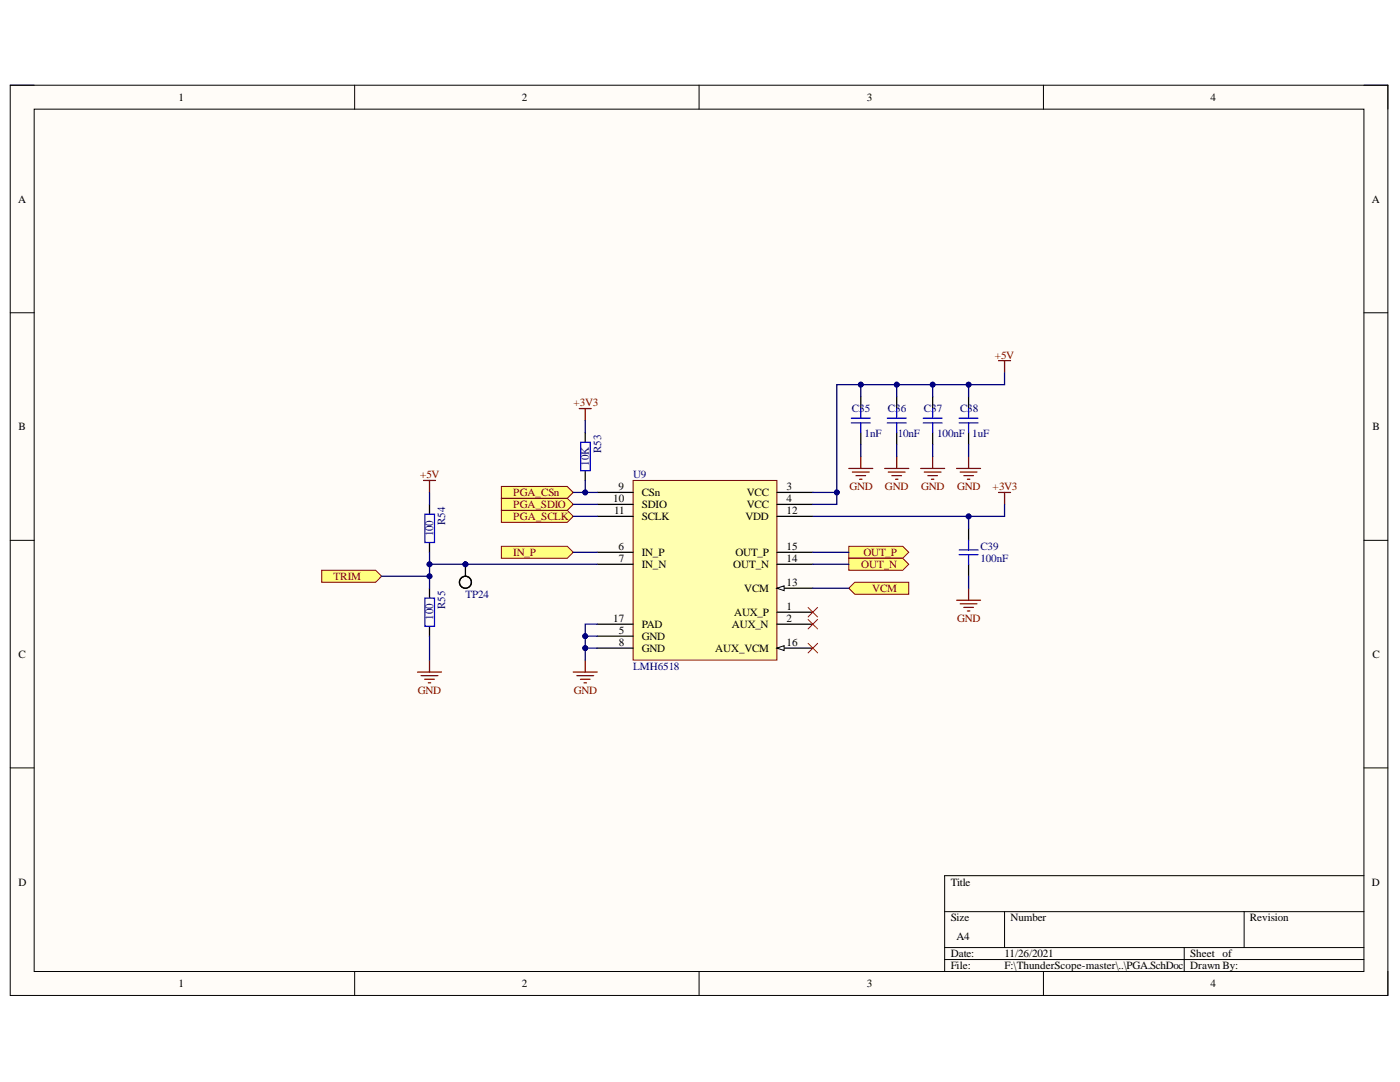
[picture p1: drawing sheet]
<svg xmlns="http://www.w3.org/2000/svg" width="279mm" height="216mm" viewBox="0 0 279 216" stroke-linecap="round" stroke-linejoin="round" font-family="sans-serif">
<defs><g id="words">
<g font-size="2.2">
<text x="35.6" y="20.1">1</text>
<text x="104.1" y="20.1">2</text>
<text x="173" y="20.1">3</text>
<text x="241.6" y="20.1">4</text>
<text x="3.6" y="40.4">A</text>
<text x="273.8" y="40.4">A</text>
<text x="3.7" y="85.8">B</text>
<text x="273.9" y="85.8">B</text>
<text x="122.4" y="100.2">10</text>
<text x="123.4" y="97.8">9</text>
<text x="128.1" y="99">CSn</text>
<text x="128.1" y="101.4">SDIO</text>
<text x="149" y="99">VCC</text>
<text x="149" y="101.4">VCC</text>
<text x="157" y="97.8">3</text>
<text x="157" y="100.2">4</text>
<text x="122.6" y="102.6">11</text>
<text x="128.1" y="103.8">SCLK</text>
<text x="148.8" y="103.8">VDD</text>
<text x="157" y="102.6">12</text>
<text x="123.4" y="109.8">6</text>
<text x="123.5" y="112.1">7</text>
<text x="128.1" y="110.9">IN_P</text>
<text x="128.1" y="113.4">IN_N</text>
<text x="146.3" y="113.4">OUT_N</text>
<text x="146.8" y="110.9">OUT_P</text>
<text x="157" y="112.1">14</text>
<text x="157" y="109.8">15</text>
<text x="148.5" y="118.1">VCM</text>
<text x="157" y="116.9">13</text>
<text x="122.4" y="124.1">17</text>
<text x="128.1" y="125.3">PAD</text>
<text x="146.1" y="125.3">AUX_N</text>
<text x="146.5" y="123">AUX_P</text>
<text x="157" y="121.7">1</text>
<text x="157" y="124.1">2</text>
<text x="3.7" y="131.3">C</text>
<text x="123.5" y="128.9">8</text>
<text x="123.5" y="126.5">5</text>
<text x="128.1" y="130.1">GND</text>
<text x="128.1" y="127.7">GND</text>
<text x="142.7" y="130.1">AUX_VCM</text>
<text x="157" y="128.9">16</text>
<text x="273.9" y="131.3">C</text>
<text x="3.7" y="176.7">D</text>
<text x="189.7" y="176.7">Title</text>
<text x="273.8" y="176.7">D</text>
<text x="189.7" y="183.8">Size</text>
<text x="201.7" y="183.8">Number</text>
<text x="249.4" y="183.8">Revision</text>
<text x="189.7" y="191">Date:</text>
<text x="190.9" y="187.5">A4</text>
<text x="200.5" y="191">11/26/2021</text>
<text x="237.5" y="191">Sheet of</text>
<text x="35.6" y="197">1</text>
<text x="104.1" y="197">2</text>
<text x="173" y="197">3</text>
<text x="189.7" y="193.4">File:</text>
<text x="200.5" y="193.4">F:\ThunderScope-master\..\PGA.SchDoc</text>
<text x="237.5" y="193.4">Drawn By:</text>
<text x="241.6" y="197">4</text>
</g>
<g font-size="2.2" fill="#800000">
<text x="198.5" y="71.5">+5V</text>
<text x="114.4" y="81.1">+3V3</text>
<text x="83.8" y="95.5">+5V</text>
<text x="102.4" y="99">PGA_CSn</text>
<text x="102.4" y="101.4">PGA_SDIO</text>
<text x="169.5" y="97.8">GND</text>
<text x="176.6" y="97.8">GND</text>
<text x="183.8" y="97.8">GND</text>
<text x="191" y="97.8">GND</text>
<text x="198.1" y="97.8">+3V3</text>
<text x="102.4" y="103.8">PGA_SCLK</text>
<text x="102.4" y="110.9">IN_P</text>
<text x="171.9" y="113.4">OUT_N</text>
<text x="172.3" y="110.9">OUT_P</text>
<text x="66.6" y="115.8">TRIM</text>
<text x="174.1" y="118.1">VCM</text>
<text x="191" y="124.1">GND</text>
<text x="83.4" y="138.4">GND</text>
<text x="114.5" y="138.4">GND</text>
</g>
<g font-size="2.2" fill="#000080">
<text x="170" y="82.3">C35</text>
<text x="177.2" y="82.3">C36</text>
<text x="184.4" y="82.3">C37</text>
<text x="191.6" y="82.3">C38</text>
<text x="172.6" y="87.1">1nF</text>
<text x="179.2" y="87.1">10nF</text>
<text x="187" y="87.1">100nF</text>
<text x="194" y="87.1">1uF</text>
<text x="117.5" y="92.9" transform="rotate(-90 117.5 92.9)">10K</text>
<text x="119.9" y="90.4" transform="rotate(-90 119.9 90.4)">R53</text>
<text x="126.4" y="95.5">U9</text>
<text x="86.4" y="107" transform="rotate(-90 86.4 107)">100</text>
<text x="88.8" y="104.8" transform="rotate(-90 88.8 104.8)">R54</text>
<text x="195.6" y="109.8">C39</text>
<text x="195.6" y="112.1">100nF</text>
<text x="92.9" y="119.3">TP24</text>
<text x="86.4" y="123.7" transform="rotate(-90 86.4 123.7)">100</text>
<text x="88.8" y="121.5" transform="rotate(-90 88.8 121.5)">R55</text>
<text x="126.4" y="133.7">LMH6518</text>
</g>
</g></defs>
<path d="M2 17h275v181.6h-275z" fill-rule="evenodd" fill="#fffcf8"/>
<path d="M2 17h275v181.6h-275z" fill="none" stroke="#000" stroke-width=".2"/>
<path d="M6.8 21.8h265.4v172.1h-265.4z" fill-rule="evenodd" fill="#fffcf8"/>
<g fill="none" stroke="#000" stroke-width=".2">
<path d="M2 17h4.8M70.8 17v4.8M139.5 17v4.8M208.2 17v4.8M272.2 17h4.8v4.8M6.8 21.8h265.4v172.1h-265.4zM2 62.4h4.8M272.2 62.4h4.8M2 107.8h4.8M272.2 107.8h4.8M2 153.2h4.8M272.2 153.2h4.8"/>
<path d="M272.2 174.7h-83.7v19.2M70.8 193.9v4.7M139.5 193.9v4.7M188.5 181.9h83.7M188.5 189.1h83.7M188.5 191.5h83.7M200.5 181.9v7.2M208.2 193.9v4.7M236.3 189.1v4.8M248.3 181.9v7.2M277 193.9v4.7"/>
</g>
<path d="M126.4 95.9h28.6v35.8h-28.6z" fill-rule="evenodd" fill="#ffffb0"/>
<path d="M126.4 95.9h28.6v35.8h-28.6z" fill="none" stroke="#800000" stroke-width=".2"/>
<path d="M119.2 98.3h7.2M119.2 100.6h7.2M119.2 103h7.2M155 103h7.2M155 117.4h7.2" fill="none" stroke="#000" stroke-width=".25"/>
<path d="M155 117.4l1.5-.5v1z" fill="#f8fcff"/>
<path d="M155 117.4l1.5-.5v1z" fill="none" stroke="#000" stroke-width=".2"/>
<path d="M155 112.6h7.2M155 110.2h7.2M155 122.2h7.2M155 124.5h7.2M155 129.3h7.2" fill="none" stroke="#000" stroke-width=".25"/>
<path d="M155 129.3l1.5-.5v1z" fill="#f8fcff"/>
<path d="M155 129.3l1.5-.5v1z" fill="none" stroke="#000" stroke-width=".2"/>
<path d="M155 98.3h7.2M119.2 110.2h7.2M119.2 112.6h7.2M155 100.6h7.2M119.2 129.3h7.2M119.2 126.9h7.2M119.2 124.5h7.2" fill="none" stroke="#000" stroke-width=".25"/>
<path d="M100.1 97.1h13.1l1.2 1.2-1.2 1.2h-13.1z" fill-rule="evenodd" fill="#ffff80"/>
<path d="M100.1 97.1h13.1l1.2 1.2-1.2 1.2h-13.1z" fill="none" stroke="#800000" stroke-width=".2"/>
<path d="M116.8 86.3v1.9M116.8 94v1.9" fill="none" stroke="#000" stroke-width=".25"/>
<path d="M115.9 88.3h1.9v5.6h-1.9z" fill="none" stroke="#00f" stroke-width=".25"/>
<path d="M115.6 81.5h2.4M116.8 81.5v2.4" fill="none" stroke="#800000" stroke-width=".25"/>
<path d="M100.1 101.8h13.1l1.2 1.2-1.2 1.2h-13.1z" fill-rule="evenodd" fill="#ffff80"/>
<path d="M100.1 101.8h13.1l1.2 1.2-1.2 1.2h-13.1z" fill="none" stroke="#800000" stroke-width=".2"/>
<path d="M100.1 99.5h13.1l1.2 1.1-1.2 1.2h-13.1z" fill-rule="evenodd" fill="#ffff80"/>
<path d="M100.1 99.5h13.1l1.2 1.1-1.2 1.2h-13.1z" fill="none" stroke="#800000" stroke-width=".2"/>
<path d="M100.1 109h13.1l1.2 1.2-1.2 1.2h-13.1z" fill-rule="evenodd" fill="#ffff80"/>
<path d="M100.1 109h13.1l1.2 1.2-1.2 1.2h-13.1z" fill="none" stroke="#800000" stroke-width=".2"/>
<path d="M114.4 134.1h4.8M115.1 134.8h3.4M115.8 135.5h2M116.6 136.3h.4M116.8 131.7v2.4" fill="none" stroke="#800000" stroke-width=".25"/>
<path d="M169.4 117.4l1.2-1.2h10.8v2.4h-10.8z" fill-rule="evenodd" fill="#ffff80"/>
<path d="M169.4 117.4l1.2-1.2h10.8v2.4h-10.8z" fill="none" stroke="#800000" stroke-width=".2"/>
<path d="M169.4 109h10.8l1.2 1.2-1.2 1.2h-10.8z" fill-rule="evenodd" fill="#ffff80"/>
<path d="M169.4 109h10.8l1.2 1.2-1.2 1.2h-10.8z" fill="none" stroke="#800000" stroke-width=".2"/>
<path d="M169.4 111.4h10.8l1.2 1.2-1.2 1.2h-10.8z" fill-rule="evenodd" fill="#ffff80"/>
<path d="M169.4 111.4h10.8l1.2 1.2-1.2 1.2h-10.8z" fill="none" stroke="#800000" stroke-width=".2"/>
<g fill="none" stroke="#000" stroke-width=".25">
<path d="M171.8 79.1v2.4M179 79.1v2.4M186.1 79.1v2.4M193.3 79.1v2.4M171.8 86.3v2.4M179 86.3v2.4M186.1 86.3v2.4M193.3 86.3v2.4M85.7 100.6v1.9M85.7 108.3v1.9M85.7 117.4v1.9M193.3 105.4v2.4"/>
<path d="M193.3 112.6v2.4M85.7 125.1v1.8"/>
</g>
<g fill="none" stroke="#00f" stroke-width=".25">
<path d="M169.9 84.4h3.8M169.9 83.4h3.8M171.8 81.5v1.9M171.8 84.4v1.9M177.1 84.4h3.7M177.1 83.4h3.7M179 81.5v1.9M179 84.4v1.9M184.3 84.4h3.7M184.3 83.4h3.7M186.1 81.5v1.9M186.1 84.4v1.9"/>
<path d="M191.4 84.4h3.8M191.4 83.4h3.8M193.3 81.5v1.9M193.3 84.4v1.9M84.8 102.6h1.9v5.7h-1.9zM84.8 119.3h1.9v5.7h-1.9zM191.4 110.7h3.8M191.4 109.7h3.8M193.3 107.8v1.9M193.3 110.7v1.9"/>
</g>
<g fill="none" stroke="#800000" stroke-width=".25">
<path d="M199.3 72h2.4M200.5 72v2.4M84.5 95.9h2.4M85.7 95.9v2.4M169.4 93.5h4.8M170.1 94.2h3.4M170.8 94.9h1.9M171.5 95.6h.5M171.8 91.1v2.4M176.6 93.5h4.8M177.3 94.2h3.3M178 94.9h1.9"/>
<path d="M178.7 95.6h.5M179 91.1v2.4M183.7 93.5h4.8M184.5 94.2h3.3M185.2 94.9h1.9M185.9 95.6h.5M186.1 91.1v2.4M190.9 93.5h4.8M191.6 94.2h3.4M192.4 94.9h1.9M193.1 95.6h.4M193.3 91.1v2.4"/>
<path d="M199.3 98.3h2.4M200.5 98.3v2.4M190.9 119.8h4.8M193.3 117.4v2.4M83.3 134.1h4.8M84 134.8h3.4M84.8 135.5h1.9M85.5 136.3h.5M85.7 131.7v2.4M191.6 120.5h3.4M192.4 121.2h1.9M193.1 121.9h.4"/>
</g>
<path d="M161.3 121.2l1.9 1.9M161.3 123.6l1.9 1.9M161.3 128.4l1.9 1.9M163.2 121.2l-1.9 1.9M163.2 123.6l-1.9 1.9M163.2 128.4l-1.9 1.9" fill="none" stroke="#f00" stroke-width=".2"/>
<path d="M64.2 113.8h10.8l1.2 1.2-1.2 1.2h-10.8z" fill-rule="evenodd" fill="#ffff80"/>
<path d="M64.2 113.8h10.8l1.2 1.2-1.2 1.2h-10.8z" fill="none" stroke="#800000" stroke-width=".2"/>
<path d="M193.3 76.8v2.3" fill="none" stroke="#000080" stroke-width=".25"/>
<circle cx="193.3" cy="76.7" r=".48" fill="#000080"/>
<circle cx="193.3" cy="76.7" r=".48" fill="none" stroke="#000080" stroke-width=".2"/>
<path d="M76.2 115h9.5" fill="none" stroke="#000080" stroke-width=".25"/>
<circle cx="85.7" cy="115" r=".48" fill="#000080"/>
<circle cx="85.7" cy="115" r=".48" fill="none" stroke="#000080" stroke-width=".2"/>
<path d="M85.7 112.6h33.5" fill="none" stroke="#000080" stroke-width=".25"/>
<circle cx="92.9" cy="112.6" r=".48" fill="#000080"/>
<circle cx="92.9" cy="112.6" r=".48" fill="none" stroke="#000080" stroke-width=".2"/>
<circle cx="85.7" cy="112.6" r=".48" fill="#000080"/>
<circle cx="85.7" cy="112.6" r=".48" fill="none" stroke="#000080" stroke-width=".2"/>
<path d="M114.4 98.3h4.8M114.4 110.2h4.8M114.4 103h4.8M114.4 100.6h4.8" fill="none" stroke="#000080" stroke-width=".25"/>
<circle cx="116.8" cy="98.3" r=".48" fill="#000080"/>
<circle cx="116.8" cy="98.3" r=".48" fill="none" stroke="#000080" stroke-width=".2"/>
<path d="M119.2 124.5h-2.4v4.8h2.4" fill="none" stroke="#000080" stroke-width=".25"/>
<circle cx="116.8" cy="126.9" r=".48" fill="#000080"/>
<circle cx="116.8" cy="126.9" r=".48" fill="none" stroke="#000080" stroke-width=".2"/>
<circle cx="116.8" cy="129.3" r=".48" fill="#000080"/>
<circle cx="116.8" cy="129.3" r=".48" fill="none" stroke="#000080" stroke-width=".2"/>
<path d="M116.8 126.9h2.4" fill="none" stroke="#000080" stroke-width=".25"/>
<circle cx="116.8" cy="126.9" r=".48" fill="#000080"/>
<circle cx="116.8" cy="126.9" r=".48" fill="none" stroke="#000080" stroke-width=".2"/>
<path d="M162.2 117.4h7.2M162.2 112.6h7.2M162.2 110.2h7.2M200.5 100.7v2.3h-38.3" fill="none" stroke="#000080" stroke-width=".25"/>
<circle cx="193.3" cy="103" r=".48" fill="#000080"/>
<circle cx="193.3" cy="103" r=".48" fill="none" stroke="#000080" stroke-width=".2"/>
<path d="M171.8 76.7h-4.8v23.9h-4.8" fill="none" stroke="#000080" stroke-width=".25"/>
<circle cx="171.8" cy="76.7" r=".48" fill="#000080"/>
<circle cx="171.8" cy="76.7" r=".48" fill="none" stroke="#000080" stroke-width=".2"/>
<circle cx="167" cy="98.3" r=".48" fill="#000080"/>
<circle cx="167" cy="98.3" r=".48" fill="none" stroke="#000080" stroke-width=".2"/>
<path d="M162.2 98.3h4.8" fill="none" stroke="#000080" stroke-width=".25"/>
<circle cx="167" cy="98.3" r=".48" fill="#000080"/>
<circle cx="167" cy="98.3" r=".48" fill="none" stroke="#000080" stroke-width=".2"/>
<path d="M179 76.8h-7.2v2.3" fill="none" stroke="#000080" stroke-width=".25"/>
<circle cx="171.8" cy="76.7" r=".48" fill="#000080"/>
<circle cx="171.8" cy="76.7" r=".48" fill="none" stroke="#000080" stroke-width=".2"/>
<circle cx="179" cy="76.7" r=".48" fill="#000080"/>
<circle cx="179" cy="76.7" r=".48" fill="none" stroke="#000080" stroke-width=".2"/>
<path d="M186.1 76.8h-7.1v2.3" fill="none" stroke="#000080" stroke-width=".25"/>
<circle cx="179" cy="76.7" r=".48" fill="#000080"/>
<circle cx="179" cy="76.7" r=".48" fill="none" stroke="#000080" stroke-width=".2"/>
<circle cx="186.1" cy="76.7" r=".48" fill="#000080"/>
<circle cx="186.1" cy="76.7" r=".48" fill="none" stroke="#000080" stroke-width=".2"/>
<path d="M200.5 74.4v2.4h-14.4v2.3" fill="none" stroke="#000080" stroke-width=".25"/>
<circle cx="186.1" cy="76.7" r=".48" fill="#000080"/>
<circle cx="186.1" cy="76.7" r=".48" fill="none" stroke="#000080" stroke-width=".2"/>
<circle cx="193.3" cy="76.7" r=".48" fill="#000080"/>
<circle cx="193.3" cy="76.7" r=".48" fill="none" stroke="#000080" stroke-width=".2"/>
<path d="M85.7 110.2v7.2M85.7 126.9v4.8" fill="none" stroke="#000080" stroke-width=".25"/>
<circle cx="85.7" cy="115" r=".48" fill="#000080"/>
<circle cx="85.7" cy="115" r=".48" fill="none" stroke="#000080" stroke-width=".2"/>
<circle cx="85.7" cy="112.6" r=".48" fill="#000080"/>
<circle cx="85.7" cy="112.6" r=".48" fill="none" stroke="#000080" stroke-width=".2"/>
<path d="M85.7 98.3v2.3M116.8 129.3v2.4" fill="none" stroke="#000080" stroke-width=".25"/>
<circle cx="116.8" cy="129.3" r=".48" fill="#000080"/>
<circle cx="116.8" cy="129.3" r=".48" fill="none" stroke="#000080" stroke-width=".2"/>
<path d="M116.8 95.9v2.4" fill="none" stroke="#000080" stroke-width=".25"/>
<circle cx="116.8" cy="98.3" r=".48" fill="#000080"/>
<circle cx="116.8" cy="98.3" r=".48" fill="none" stroke="#000080" stroke-width=".2"/>
<path d="M116.8 83.9v2.4M171.8 88.7v2.4M179 88.7v2.4M186.1 88.7v2.4M193.3 103v2.4M193.3 115v2.4" fill="none" stroke="#000080" stroke-width=".25"/>
<circle cx="193.3" cy="103" r=".48" fill="#000080"/>
<circle cx="193.3" cy="103" r=".48" fill="none" stroke="#000080" stroke-width=".2"/>
<path d="M193.3 88.7v2.4" fill="none" stroke="#000080" stroke-width=".25"/>
<circle cx="92.9" cy="112.6" r=".48" fill="#000080"/>
<circle cx="92.9" cy="112.6" r=".48" fill="none" stroke="#000080" stroke-width=".2"/>
<path d="M92.9 112.6v2.4" fill="none" stroke="#000" stroke-width=".25"/>
<circle cx="92.9" cy="112.6" r=".48" fill="#000080"/>
<circle cx="92.9" cy="112.6" r=".48" fill="none" stroke="#000080" stroke-width=".2"/>
<circle cx="92.9" cy="116.2" r="1.2" fill="none" stroke="#000" stroke-width=".25"/>
<use href="#words"/>
</svg>
